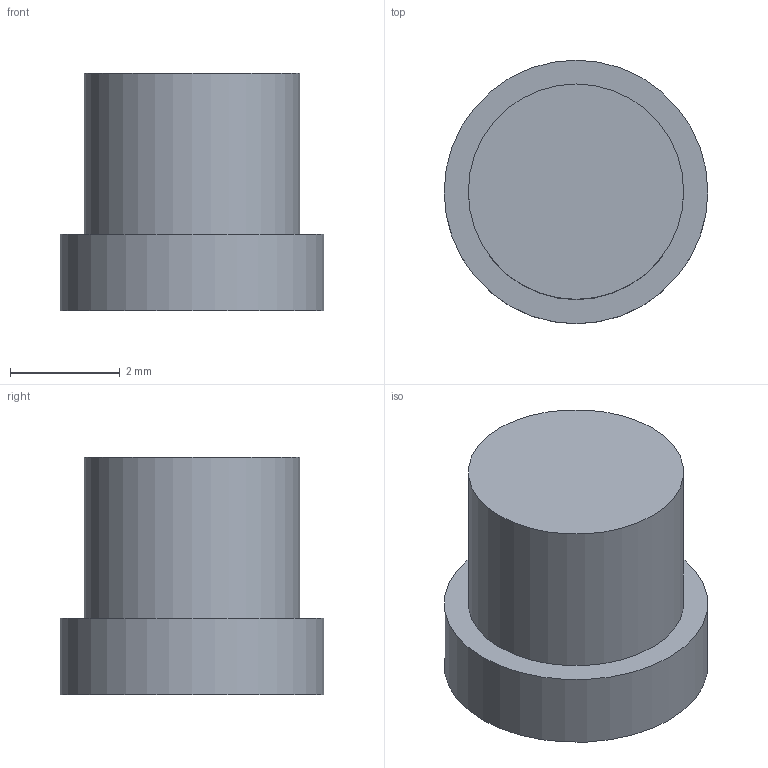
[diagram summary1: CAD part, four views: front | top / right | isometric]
STEP (ISO 10303-21) file: header records copied from the file, then geometry measured from it (millimetres).
FILE_DESCRIPTION(('FreeCAD Model'),'2;1');
FILE_NAME('Open CASCADE Shape Model','2021-05-23T22:20:11',('Author'),( ''),'Open CASCADE STEP processor 7.5','FreeCAD','Unknown');
FILE_SCHEMA(('AUTOMOTIVE_DESIGN { 1 0 10303 214 1 1 1 1 }'));
Length unit declared in the file: millimetre
Products named in the file (3): PT111G2DisassemblingLatchPin; cylinder; cylinder001
Assembly tree (2 placements, depth 2):
  PT111G2DisassemblingLatchPin
    cylinder
    cylinder001
Bounding box: 4.81 x 4.81 x 4.34 mm (x, y, z)
Volume: 61.1 mm3; surface area: 118.1 mm2
Topology: 2 solids, 2 shells, 6 faces, 6 edges, 4 vertices
Faces by surface type: plane 4, cylinder 2
Full cylindrical faces by diameter (mm): 3.93 x1, 4.81 x1
Entity records: 258 total; most frequent: DIRECTION 40, CARTESIAN_POINT 31, AXIS2_PLACEMENT_3D 13, ORIENTED_EDGE 12, PCURVE 12, DEFINITIONAL_REPRESENTATION 12, LINE 10, VECTOR 10
One B-rep face of a CAD part: STEP entity #237.
In plain terms, the planar face has unit normal (0, 0, 1).
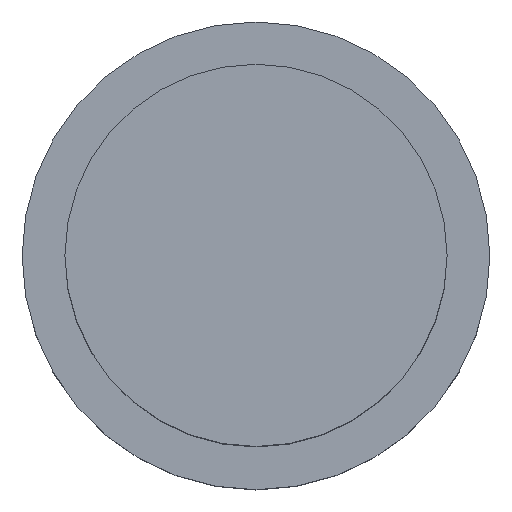
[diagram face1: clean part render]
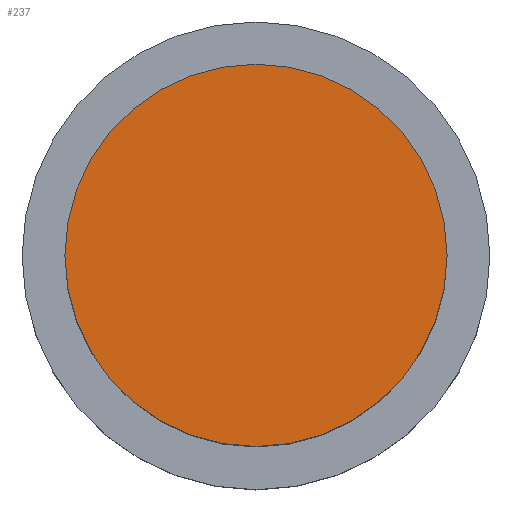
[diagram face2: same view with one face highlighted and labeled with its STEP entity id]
Its self-contained STEP definition (entity closure, numbers rounded to 3 decimals):
#153 = EDGE_CURVE('',#154,#154,#156,.T.);
#154 = VERTEX_POINT('',#155);
#155 = CARTESIAN_POINT('',(1.965,0.,2.94));
#156 = SURFACE_CURVE('',#157,(#162,#174),.PCURVE_S1.);
#157 = CIRCLE('',#158,1.965);
#158 = AXIS2_PLACEMENT_3D('',#159,#160,#161);
#159 = CARTESIAN_POINT('',(0.,0.,2.94));
#160 = DIRECTION('',(0.,0.,1.));
#161 = DIRECTION('',(1.,0.,-0.));
#162 = PCURVE('',#163,#168);
#163 = CYLINDRICAL_SURFACE('',#164,1.965);
#164 = AXIS2_PLACEMENT_3D('',#165,#166,#167);
#165 = CARTESIAN_POINT('',(0.,0.,0.));
#166 = DIRECTION('',(0.,0.,1.));
#167 = DIRECTION('',(1.,0.,-0.));
#168 = DEFINITIONAL_REPRESENTATION('',(#169),#173);
#169 = LINE('',#170,#171);
#170 = CARTESIAN_POINT('',(0.,2.94));
#171 = VECTOR('',#172,1.);
#172 = DIRECTION('',(1.,0.));
#173 = ( GEOMETRIC_REPRESENTATION_CONTEXT(2) 
PARAMETRIC_REPRESENTATION_CONTEXT() REPRESENTATION_CONTEXT('2D SPACE',''
  ) );
#174 = PCURVE('',#175,#180);
#175 = PLANE('',#176);
#176 = AXIS2_PLACEMENT_3D('',#177,#178,#179);
#177 = CARTESIAN_POINT('',(0.,0.,2.94));
#178 = DIRECTION('',(0.,0.,1.));
#179 = DIRECTION('',(1.,0.,-0.));
#180 = DEFINITIONAL_REPRESENTATION('',(#181),#185);
#181 = CIRCLE('',#182,1.965);
#182 = AXIS2_PLACEMENT_2D('',#183,#184);
#183 = CARTESIAN_POINT('',(0.,0.));
#184 = DIRECTION('',(1.,0.));
#185 = ( GEOMETRIC_REPRESENTATION_CONTEXT(2) 
PARAMETRIC_REPRESENTATION_CONTEXT() REPRESENTATION_CONTEXT('2D SPACE',''
  ) );
#237 = ADVANCED_FACE('',(#238),#175,.T.);
#238 = FACE_BOUND('',#239,.T.);
#239 = EDGE_LOOP('',(#240));
#240 = ORIENTED_EDGE('',*,*,#153,.T.);
